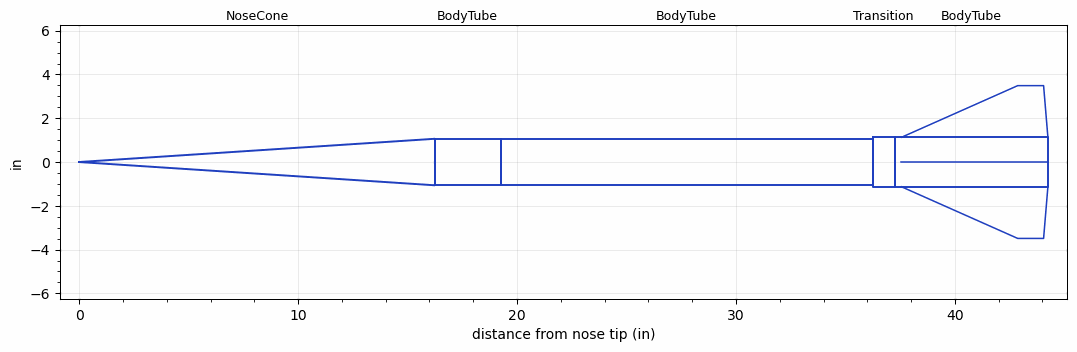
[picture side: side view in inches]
<RASAeroDocument>
 <FileVersion>2</FileVersion>
 <RocketDesign>
  <NoseCone>
   <Length>16.25</Length>
   <Diameter>2.125</Diameter>
   <Shape>Conical</Shape>
   <BluntRadius>0.08</BluntRadius>
   <Location>0</Location>
  </NoseCone>
  <BodyTube>
   <Length>3</Length>
   <Diameter>2.125</Diameter>
   <Location>16.25</Location>
  </BodyTube>
  <BodyTube>
   <Length>17</Length>
   <Diameter>2.125</Diameter>
   <Location>19.25</Location>
  </BodyTube>
  <Transition>
   <Length>1</Length>
   <Diameter>2.255</Diameter>
   <Location>36.25</Location>
   <RearDiameter>2.255</RearDiameter>
  </Transition>
  <BodyTube>
   <Length>7</Length>
   <Diameter>2.255</Diameter>
   <Location>37.25</Location>
   <Fin>
    <Count>4</Count>
    <Chord>6.6929</Chord>
    <Span>2.3622</Span>
    <SweepDistance>5.3149</SweepDistance>
    <TipChord>1.1811</TipChord>
    <Thickness>0.1575</Thickness>
    <LERadius>0.032</LERadius>
    <Location>6.6929</Location>
    <AirfoilSection>Hexagonal</AirfoilSection>
    <FX1>0.75</FX1>
    <FX3>0.75</FX3>
   </Fin>
  </BodyTube>
  <Surface>Smooth Paint</Surface>
  <ModifiedBarrowman>True</ModifiedBarrowman>
  <Turbulence>True</Turbulence>
  <UseBooster1>False</UseBooster1>
  <UseBooster2>False</UseBooster2>
 </RocketDesign>
 <LaunchSite>
  <Altitude>2000</Altitude>
  <Pressure>27.83</Pressure>
  <RodAngle>0</RodAngle>
  <RodLength>96</RodLength>
  <Temperature>51.87</Temperature>
  <WindSpeed>20</WindSpeed>
 </LaunchSite>
 <Recovery>
  <Altitude1>0</Altitude1>
  <Altitude2>0</Altitude2>
  <DeviceType1>None</DeviceType1>
  <DeviceType2>None</DeviceType2>
  <Event1>False</Event1>
  <Event2>False</Event2>
  <Size1>0</Size1>
  <Size2>0</Size2>
  <EventType1>None</EventType1>
  <EventType2>None</EventType2>
  <CD1>0</CD1>
  <CD2>0</CD2>
 </Recovery>
 <SimulationList>
  <Simulation>
   <SustainerEngine>K3000  (VulpesHLBL)</SustainerEngine>
   <SustainerLaunchWt>8.92</SustainerLaunchWt>
   <SustainerNozzleDiameter>1.25</SustainerNozzleDiameter>
   <SustainerCG>26</SustainerCG>
   <SustainerIgnitionDelay>0</SustainerIgnitionDelay>
   <Booster1SeparationDelay>0</Booster1SeparationDelay>
   <Booster1IgnitionDelay>0</Booster1IgnitionDelay>
   <IncludeBooster1>False</IncludeBooster1>
   <Booster2Delay>0</Booster2Delay>
   <IncludeBooster2>False</IncludeBooster2>
   <TimetoApogee>32.12062</TimetoApogee>
   <MaxAltitude>22855.87</MaxAltitude>
   <MaxVelocity>2416.982</MaxVelocity>
  </Simulation>
  <Simulation>
   <SustainerLaunchWt>6.509</SustainerLaunchWt>
   <SustainerCG>29.975</SustainerCG>
   <SustainerIgnitionDelay>0</SustainerIgnitionDelay>
   <Booster1SeparationDelay>0</Booster1SeparationDelay>
   <Booster1IgnitionDelay>0</Booster1IgnitionDelay>
   <IncludeBooster1>False</IncludeBooster1>
   <Booster2Delay>0</Booster2Delay>
   <IncludeBooster2>False</IncludeBooster2>
  </Simulation>
  <Simulation>
   <SustainerLaunchWt>6.46</SustainerLaunchWt>
   <SustainerCG>29.9616</SustainerCG>
   <SustainerIgnitionDelay>0</SustainerIgnitionDelay>
   <Booster1SeparationDelay>0</Booster1SeparationDelay>
   <Booster1IgnitionDelay>0</Booster1IgnitionDelay>
   <IncludeBooster1>False</IncludeBooster1>
   <Booster2Delay>0</Booster2Delay>
   <IncludeBooster2>False</IncludeBooster2>
  </Simulation>
 </SimulationList>
</RASAeroDocument>
